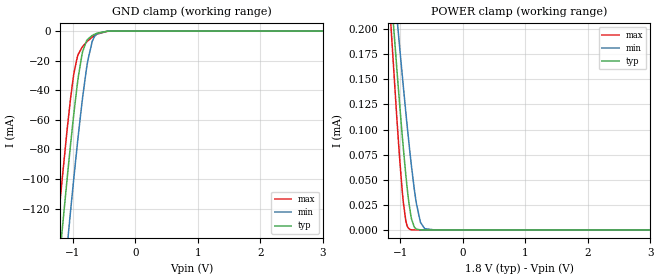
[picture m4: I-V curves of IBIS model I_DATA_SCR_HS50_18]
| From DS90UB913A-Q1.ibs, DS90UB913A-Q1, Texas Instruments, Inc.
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|   Model I_DATA_SCR_HS50_18
[Model] I_DATA_SCR_HS50_18
Model_type Input
Vinl =   0.63
Vinh =   1.17
|   typ   min   max
|   (nom)   (fast)   (slow)
C_comp   0.5298pF   0.3665pF   0.5298pF
[Temperature Range]   25.000   105.000   -40.000
[Voltage Range]   1.800V   1.7100V   1.8900V
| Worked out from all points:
|   GND clamp passes 1 mA (typ) near -0.56 V on its own axis
[GND Clamp]
|   Voltage   I(typ)   I(min)   I(max)
-1.8V     -430.9mA   -477mA     -396.6mA
-1.238V   -164.5mA   -211.3mA   -129.6mA
-1.174V   -135.2mA   -181.7mA   -100.7mA
-1.093V   -99.54mA   -145.4mA   -66.37mA
-1.039V   -76.81mA   -121.8mA   -45.69mA
-984.6mV  -55.39mA   -98.86mA   -28.59mA
-930.6mV  -36.12mA   -76.78mA   -17.61mA
-855mV    -15.77mA   -48.21mA   -11.06mA
-763.2mV  -5.498mA   -20.14mA   -6.658mA
-687.6mV  -2.877mA   -6.556mA   -3.945mA
-450mV    -97.64uA   -77.9uA    -176.8uA
3.595V    0A         0A         0A
[POWER Clamp]
|   Voltage   I(typ)   I(min)   I(max)
-1.8V     803.7uA    754.7uA    897.4uA
-1.157V   241.8uA    282.5uA    208.5uA
-1.055V   157.9uA    210.7uA    108.4uA
-1.012V   124.1uA    181.2uA    70.17uA
-952.2mV  80.3uA     141.7uA    26.6uA
-914.4mV  55uA       117.4uA    9.25uA
-865.8mV  27.6uA     87.52uA    1.228uA
-822.6mV  10.92uA    62.89uA    149.1nA
-747mV    921.8nA    26.99uA    1.513nA
-682.2mV  75.41nA    8.215uA    0A
-612mV    3.441nA    1.296uA    0A
3.595V    0A         0A         0A
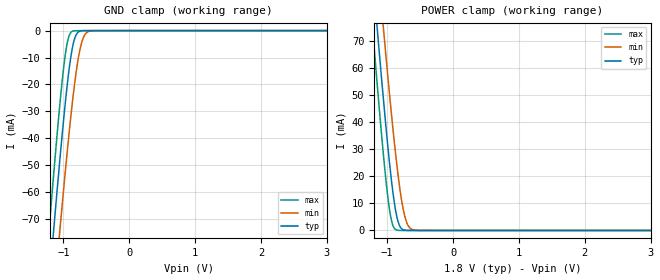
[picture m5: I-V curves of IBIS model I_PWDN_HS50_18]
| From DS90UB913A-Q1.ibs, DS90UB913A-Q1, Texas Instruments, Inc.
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|   Model I_PWDN_HS50_18
[Model]   I_PWDN_HS50_18
Model_type   Input
Vinl = 0.63V
Vinh = 1.17V
|   typ   min   max
|   (nom)   (weak)   (fast)
C_comp   0.5928pF   0.5928pF   0.5928pF
[Voltage Range]   1.800V   1.710V   1.890V
[Temperature Range]   25.0   105.0   -40.0
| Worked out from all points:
|   GND clamp passes 1 mA (typ) near -0.79 V on its own axis
|   POWER clamp passes 1 mA (typ) near -0.79 V on its own axis
[GND Clamp]
|   Voltage   I(typ)   I(min)   I(max)
-1.8V     -270.9mA   -291mA     -255.6mA
-1.228V   -97.1mA    -122.7mA   -76.77mA
-1.201V   -89.21mA   -115mA     -68.71mA
-1.147V   -73.63mA   -99.73mA   -52.87mA
-1.055V   -48.06mA   -74.39mA   -27.51mA
-957.6mV  -23.54mA   -48.82mA   -6.663mA
-871.2mV  -7.328mA   -28.21mA   -335.2uA
-811.8mV  -1.781mA   -16.28mA   -25.67uA
-741.6mV  -161.6uA   -6.205mA   -6.921uA
-682.2mV  -20.1uA    -1.83mA    -5.854uA
-601.2mV  -4.02uA    -199.2uA   -5.127uA
3.595V    6.712uA    3.483uA    12.03uA
[POWER Clamp]
|   Voltage   I(typ)   I(min)   I(max)
-1.8V     270.2mA    290.2mA    254.8mA
-1.228V   96.77mA    122.3mA    76.49mA
-1.201V   88.9mA     114.6mA    68.45mA
-1.147V   73.36mA    99.39mA    52.65mA
-1.055V   47.86mA    74.11mA    27.37mA
-957.6mV  23.41mA    48.61mA    6.6mA
-871.2mV  7.262mA    28.06mA    325.8uA
-811.8mV  1.758mA    16.17mA    20.65uA
-741.6mV  156.5uA    6.146mA    2.661uA
-682.2mV  17.07uA    1.807mA    2.011uA
-601.2mV  1.608uA    195uA      1.824uA
3.595V    0A         0A         0A
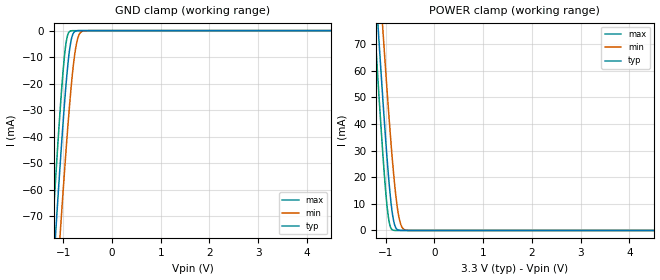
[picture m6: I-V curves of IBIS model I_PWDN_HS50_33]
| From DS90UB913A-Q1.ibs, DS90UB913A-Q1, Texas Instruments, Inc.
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|   Model I_PWDN_HS50_33
[Model]   I_PWDN_HS50_33
Model_type   Input
Vinl = 0.8V
Vinh = 2.0V
|   typ   min   max
|   (nom)   (weak)   (fast)
C_comp   0.5928pF   0.5928pF   0.5928pF
[Voltage Range]   3.300V   3.000V   3.600V
[Temperature Range]   25.0   105.0   -40.0
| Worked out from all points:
|   GND clamp passes 1 mA (typ) near -0.79 V on its own axis
|   POWER clamp passes 1 mA (typ) near -0.79 V on its own axis
[GND Clamp]
|   Voltage   I(typ)   I(min)   I(max)
-3.3V     -740.6mA   -745.8mA   -738.2mA
-1.231V   -98.06mA   -123.6mA   -77.76mA
-1.221V   -95.16mA   -120.8mA   -74.79mA
-1.171V   -80.77mA   -106.7mA   -60.12mA
-1.142V   -72.26mA   -98.38mA   -51.49mA
-1.063V   -50.17mA   -76.5mA    -29.54mA
-953.7mV  -22.65mA   -47.84mA   -6.095mA
-914.1mV  -14.38mA   -38.09mA   -1.938mA
-854.7mV  -5.279mA   -24.66mA   -158.3uA
-735.9mV  -131.2uA   -5.62mA    -6.724uA
-597.3mV  -3.893uA   -177.7uA   -5.09uA
6.59V     7.865uA    3.955uA    14.61uA
[POWER Clamp]
|   Voltage   I(typ)   I(min)   I(max)
-3.3V     739mA      744.2mA    736.5mA
-1.231V   97.8mA     123.3mA    77.52mA
-1.221V   94.9mA     120.5mA    74.56mA
-1.171V   80.54mA    106.4mA    59.92mA
-1.142V   72.04mA    98.11mA    51.31mA
-1.063V   50mA       76.28mA    29.42mA
-953.7mV  22.55mA    47.67mA    6.048mA
-914.1mV  14.3mA     37.95mA    1.916mA
-854.7mV  5.24mA     24.55mA    149.8uA
-735.9mV  126.1uA    5.58mA     498.8nA
-597.3mV  637nA      174.2uA    50.05nA
6.59V     0A         0A         0A
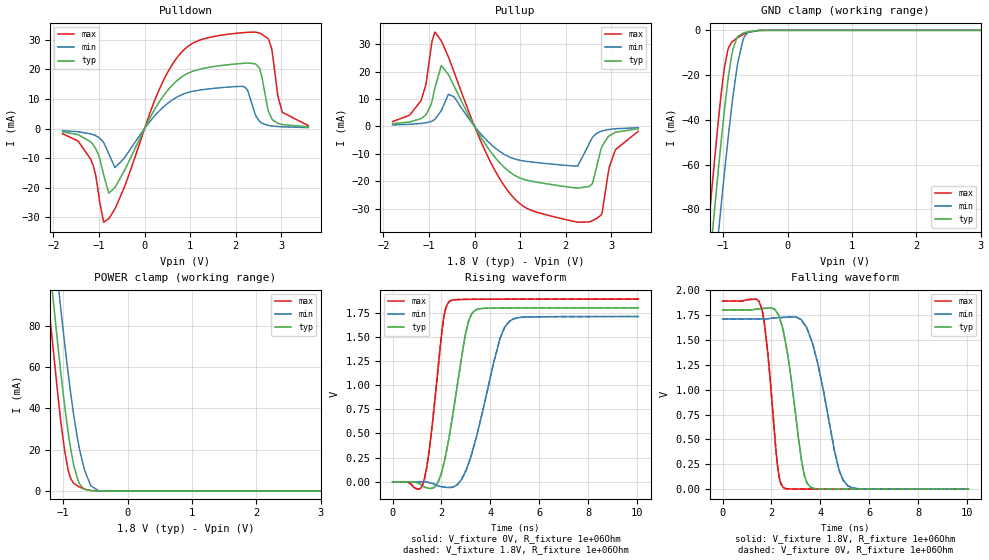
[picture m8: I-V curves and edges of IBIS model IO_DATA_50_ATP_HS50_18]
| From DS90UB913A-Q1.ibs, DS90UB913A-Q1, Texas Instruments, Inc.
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|   Model IO_DATA_50_ATP_HS50_18
[Model]  IO_DATA_50_ATP_HS50_18
Model_type   I/O
Polarity   Non-Inverting
Enable   Active-Low
Vinl =   0.63
Vinh =   1.17
Vmeas = 0.9V
|   typ   min   max
|   (nom)   (fast)   (slow)
C_comp   1.107pF   1.107pF   1.107pF
[Temperature Range]   25.000   105.00   -40.000
[Voltage Range]   1.800V   1.700V   1.900V
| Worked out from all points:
|   slope of the pulldown table from 0 to 0.27 V, typ, clamps not added: 35 ohm
|   slope of the pullup table from 0 to 0.27 V, typ, clamps not added: 37 ohm
|   GND clamp passes 1 mA (typ) near -0.66 V on its own axis
|   POWER clamp passes 1 mA (typ) near -0.68 V on its own axis
|   falling waveform, V_fixture 1.8V, R_fixture 1e+06Ohm: 20-80 % time 589ps typ, 837ps min, 405ps max; typ from 1.8 V to 0 V
|   rising waveform, V_fixture 0V, R_fixture 1e+06Ohm: 20-80 % time 684ps typ, 979ps min, 474ps max; typ from 0 V to 1.8 V
|   rising waveform, V_fixture 1.8V, R_fixture 1e+06Ohm: 20-80 % time 684ps typ, 979ps min, 474ps max; typ from 0 V to 1.8 V
|   falling waveform, V_fixture 0V, R_fixture 1e+06Ohm: 20-80 % time 589ps typ, 837ps min, 405ps max; typ from 1.8 V to 0 V
[Pulldown]
|   Voltage   I(typ)   I(min)   I(max)
-1.8V     -1.155mA   -722uA     -1.746mA
-1.184V   -4.476mA   -1.794mA   -10.29mA
-898.2mV  -15.64mA   -4.698mA   -31.64mA
-784.8mV  -21.82mA   -8.552mA   -30.46mA
-649.8mV  -19.91mA   -13.23mA   -27.17mA
252mV     7.263mA    4.813mA    10.64mA
711mV     16.19mA    10.63mA    23.93mA
2.266V    22.12mA    12.72mA    32.53mA
2.52V     20.5mA     2.492mA    32.28mA
2.817V    2.865mA    818.9uA    24.22mA
3.022V    1.333mA    582uA      5.5mA
3.595V    562.9uA    334.5uA    995.1uA
[GND Clamp]
|   Voltage   I(typ)   I(min)   I(max)
-1.8V     -296.6mA   -318.2mA   -281mA
-1.228V   -109.2mA   -137.1mA   -87.53mA
-1.168V   -90.62mA   -118.9mA   -68.54mA
-1.082V   -64.33mA   -93.04mA   -42.27mA
-1.033V   -50.2mA    -78.83mA   -28.89mA
-979.2mV  -35.42mA   -63.49mA   -16.52mA
-930.6mV  -23.5mA    -50.24mA   -9.211mA
-871.2mV  -11.85mA   -35.13mA   -5.505mA
-768.6mV  -2.676mA   -13.86mA   -3.143mA
-693mV    -1.308mA   -4.468mA   -1.9mA
-450mV    -43.26uA   -33.03uA   -89.99uA
3.595V    0A         0A         0A
[Pullup]
|   Voltage   I(typ)   I(min)   I(max)
-1.8V     960.1uA    529.2uA    1.735mA
-1.179V   2.783mA    1.043mA    9.274mA
-871.2mV  13.95mA    2.526mA    34.4mA
-730.8mV  22.21mA    5.721mA    31.27mA
-450mV    14.71mA    10.77mA    19.81mA
721.8mV   -16mA      -10.84mA   -23.32mA
2.266V    -22.55mA   -14.43mA   -34.99mA
2.585V    -20.92mA   -4.098mA   -34.41mA
2.774V    -8.357mA   -1.812mA   -32.45mA
2.957V    -3.442mA   -1.136mA   -14.88mA
3.092V    -2.174mA   -887.6uA   -8.516mA
3.595V    -844.1uA   -485.2uA   -1.766mA
[POWER Clamp]
|   Voltage   I(typ)   I(min)   I(max)
-1.8V     302.3mA    326mA      285.1mA
-1.217V   111.8mA    141.9mA    88.15mA
-1.19V    103.3mA    133.7mA    79.49mA
-1.076V   68.91mA    99.85mA    44.83mA
-1.044V   59.55mA    90.46mA    35.82mA
-919.8mV  27.87mA    56.5mA     9.944mA
-844.2mV  13.97mA    38.55mA    4.002mA
-779.4mV  6.085mA    25.78mA    2.447mA
-660.6mV  732.7uA    9.487mA    827.9uA
-568.8mV  167.5uA    2.464mA    204.4uA
-450mV    13.54uA    113.5uA    13.22uA
3.595V    0A         0A         0A
[Ramp]
R_load = 1e+06
|   typ   min   max
dV/dt_r   1.07987/6.83959e-10   1.02562/9.78811e-10   1.13394/4.74165e-10
dV/dt_f   1.07988/5.89236e-10   1.02563/8.37013e-10   1.13395/4.05042e-10
[Falling Waveform]
V_fixture = 1.8V
V_fixture_min = 1.71V
V_fixture_max = 1.89V
R_fixture = 1e+06Ohm
C_fixture = 0F
|   Time   V(typ)   V(min)   V(max)
0s        1.8V       1.71V      1.89V
1.621ns   1.814V     1.709V     1.796V
1.851ns   1.819V     1.712V     1.367V
2.234ns   1.77V      1.721V     262.1mV
2.481ns   1.593V     1.725V     16.3mV
3.23ns    284mV      1.698V     1.07mV
3.596ns   20.07mV    1.521V     761.8uV
4.778ns   976.1uV    180.4mV    359.7uV
5.117ns   791.7uV    35.57mV    290.4uV
10.05ns   126.1uV    292.8uV    71.1uV
[Rising Waveform]
V_fixture = 0V
V_fixture_min = 0V
V_fixture_max = 0V
R_fixture = 1e+06Ohm
C_fixture = 0F
|   Time   V(typ)   V(min)   V(max)
0s        41.55uV    165.9uV    9.761uV
1.225ns   -43.42mV   305.9uV    -33.09mV
1.496ns   -67.21mV   -8.484mV   317.7mV
1.887ns   10.44mV    -43.24mV   1.236V
2.091ns   183.3mV    -53.81mV   1.697V
2.313ns   460.7mV    -59.57mV   1.862V
3.23ns    1.735V     282mV      1.887V
4.392ns   1.797V     1.48V      1.889V
4.778ns   1.798V     1.66V      1.889V
10.05ns   1.8V       1.71V      1.89V
[Rising Waveform]
V_fixture = 1.8V
V_fixture_min = 1.71V
V_fixture_max = 1.89V
R_fixture = 1e+06Ohm
C_fixture = 0F
|   Time   V(typ)   V(min)   V(max)
0s        128uV      297uV      70.75uV
1.225ns   -43.45mV   433uV      -32.27mV
1.496ns   -66.51mV   -8.334mV   318.8mV
1.887ns   11.62mV    -42.79mV   1.238V
2.091ns   184.6mV    -53.06mV   1.697V
2.313ns   462.2mV    -58.52mV   1.863V
3.23ns    1.735V     283.8mV    1.888V
4.392ns   1.797V     1.482V     1.889V
4.778ns   1.798V     1.66V      1.889V
10.05ns   1.8V       1.71V      1.89V
[Falling Waveform]
|Gnd
V_fixture = 0V
V_fixture_min = 0V
V_fixture_max = 0V
R_fixture = 1e+06Ohm
C_fixture = 0F
|   Time   V(typ)   V(min)   V(max)
0s        1.8V       1.71V      1.89V
1.621ns   1.814V     1.709V     1.795V
1.851ns   1.819V     1.712V     1.366V
2.234ns   1.77V      1.721V     261.5mV
2.481ns   1.592V     1.725V     16.12mV
3.23ns    283.1mV    1.697V     983.6uV
3.596ns   19.81mV    1.52V      683.4uV
4.778ns   856.7uV    179.4mV    291.9uV
5.117ns   679.6uV    35.13mV    224.4uV
10.05ns   39.67uV    161.9uV    10.1uV
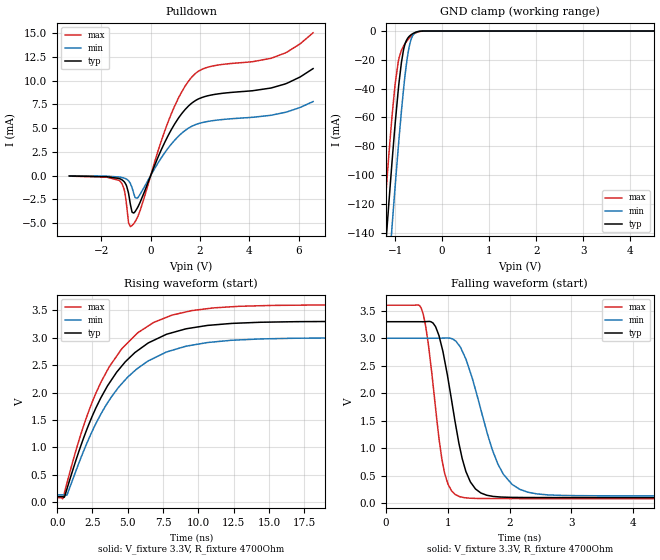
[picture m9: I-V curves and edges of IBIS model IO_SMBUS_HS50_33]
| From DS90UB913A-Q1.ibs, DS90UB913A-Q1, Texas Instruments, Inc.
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|   Model IO_SMBUS_HS50_33
[Model]  IO_SMBUS_HS50_33
Model_type I/O_open_drain
Enable   Active-High
Vinl = 0.8V
Vinh = 2.0V
Vmeas = 1.3V
Vref = 3.3
Rref = 4700
|   typ   min   max
|   (nom)   (fast)   (slow)
C_comp   2.846pF   2.827pF   2.847pF
[Temperature Range]   25.0000   105.000   -40.0000
[Voltage Range]   3.3000V   3.0000V   3.6000V
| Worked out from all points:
|   slope of the pulldown table from 0 to 0.495 V, typ, clamps not added: 161 ohm
|   GND clamp passes 1 mA (typ) near -0.57 V on its own axis
|   falling waveform, V_fixture 3.3V, R_fixture 4700Ohm: 20-80 % time 313ps typ, 462ps min, 222ps max; typ from 3.3 V to 0.101 V
|   rising waveform, V_fixture 3.3V, R_fixture 4700Ohm: 20-80 % time 3.92ns typ, 4.09ns min, 3.8ns max; typ from 0.101 V to 3.3 V
[Pulldown]
|   Voltage   I(typ)   I(min)   I(max)
-3.3V     -50.34uA   -30.88uA   -64.44uA
-1.261V   -330.2uA   -160.2uA   -563uA
-1.073V   -661.8uA   -269.1uA   -1.521mA
-894.3mV  -1.931mA   -564.1uA   -4.993mA
-825mV    -3.027mA   -830.1uA   -5.371mA
-755.7mV  -3.86mA    -1.277mA   -5.263mA
-537.9mV  -3.393mA   -2.366mA   -4.397mA
699.6mV   4.164mA    2.858mA    5.599mA
1.67V     7.624mA    5.188mA    10.36mA
2.442V    8.463mA    5.745mA    11.48mA
4.887V    9.21mA     6.344mA    12.34mA
6.59V     11.25mA    7.782mA    15.02mA
[GND Clamp]
|   Voltage   I(typ)   I(min)   I(max)
-3.3V     -1.167A    -1.21A     -1.135A
-1.251V   -172.2mA   -218.9mA   -137.3mA
-1.162V   -132.2mA   -178.5mA   -98.12mA
-1.073V   -93.94mA   -139.2mA   -61.99mA
-993.3mV  -62.34mA   -105.5mA   -35.34mA
-933.9mV  -41.3mA    -81.43mA   -21.56mA
-825mV    -13.83mA   -41.91mA   -10.68mA
-765.6mV  -6.993mA   -24.57mA   -7.626mA
-706.2mV  -3.93mA    -11.88mA   -5.147mA
-646.8mV  -2.277mA   -4.634mA   -3.183mA
-577.5mV  -1.054mA   -1.289mA   -1.568mA
6.59V     0A         0A         0A
[POWER Clamp]
|   Voltage   I(typ)   I(min)   I(max)
-3.3V     0A         0A         0A
0V        0A         0A         0A
6.59V     0A         0A         0A
[Ramp]
R_load = 4700
|   typ   min   max
dV/dt_r   1.91926/3.92426e-09   1.72026/4.09122e-09   2.11028/3.79737e-09
dV/dt_f   1.91925/3.12626e-10   1.72026/4.61695e-10   2.11029/2.21836e-10
[Falling Waveform]
V_fixture = 3.3V
V_fixture_min = 3V
V_fixture_max = 3.6V
R_fixture = 4700Ohm
C_fixture = 0F
|   Time   V(typ)   V(min)   V(max)
0s        3.3V       3V         3.6V
571ps     3.3V       3V         3.554V
805.3ps   3.21V      2.999V     1.732V
1.005ns   2.269V     3.004V     347.1mV
1.235ns   814.6mV    2.77V      109.6mV
1.463ns   249.1mV    2.013V     87.64mV
1.72ns    127.3mV    977.3mV    85.2mV
2.039ns   106.9mV    344.6mV    84.51mV
3.099ns   102.8mV    138mV      83.96mV
150ns     101.2mV    132.9mV    82.86mV
[Rising Waveform]
V_fixture = 3.3V
V_fixture_min = 3V
V_fixture_max = 3.6V
R_fixture = 4700Ohm
C_fixture = 0F
|   Time   V(typ)   V(min)   V(max)
0s        101.2mV    132.9mV    82.86mV
400.9ps   100.1mV    132.9mV    68.16mV
703.5ps   252.4mV    137.1mV    361.1mV
1.611ns   982.9mV    764.7mV    1.186V
2.589ns   1.632V     1.354V     1.896V
3.677ns   2.166V     1.856V     2.466V
4.566ns   2.482V     2.16V      2.797V
6.834ns   2.953V     2.627V     3.281V
11.07ns   3.235V     2.924V     3.546V
150ns     3.3V       3V         3.6V
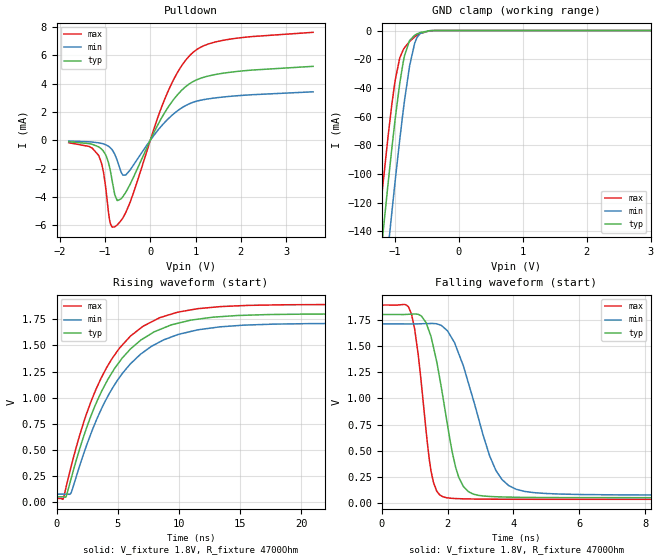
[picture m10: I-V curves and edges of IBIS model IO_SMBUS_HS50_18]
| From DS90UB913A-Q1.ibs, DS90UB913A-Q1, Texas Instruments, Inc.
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|   Model IO_SMBUS_HS50_18
[Model]  IO_SMBUS_HS50_18
Model_type I/O_open_drain
Enable   Active-High
Vinl = 0.63V
Vinh = 1.17V
Vmeas = 0.9V
Vref = 1.8V
Rref = 4700
|   typ   min   max
|   (nom)   (fast)   (slow)
C_comp   2.846pF   2.827pF   2.847pF
[Temperature Range]   25.0000   105.000   -40.0000
[Voltage Range]   1.8000V   1.7000V   1.9000V
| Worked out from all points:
|   slope of the pulldown table from 0 to 0.27 V, typ, clamps not added: 159 ohm
|   GND clamp passes 1 mA (typ) near -0.55 V on its own axis
|   falling waveform, V_fixture 1.8V, R_fixture 4700Ohm: 20-80 % time 605ps typ, 953ps min, 387ps max; typ from 1.8 V to 0.054 V
|   rising waveform, V_fixture 1.8V, R_fixture 4700Ohm: 20-80 % time 4.31ns typ, 4.54ns min, 4.17ns max; typ from 0.054 V to 1.8 V
[Pulldown]
|   Voltage   I(typ)   I(min)   I(max)
-1.8V     -104.1uA   -53.41uA   -171.3uA
-1.141V   -461.7uA   -179.9uA   -1.065mA
-1.028V   -797.8uA   -264.8uA   -2.355mA
-898.2mV  -1.902mA   -481.7uA   -5.632mA
-784.8mV  -3.843mA   -977.1uA   -6.124mA
-725.4mV  -4.267mA   -1.471mA   -5.973mA
-541.8mV  -3.682mA   -2.457mA   -5.115mA
306mV     1.89mA     1.222mA    2.806mA
608.4mV   3.247mA    2.103mA    4.837mA
910.8mV   4.087mA    2.646mA    6.118mA
1.667V    4.769mA    3.078mA    7.102mA
3.595V    5.227mA    3.427mA    7.633mA
[GND Clamp]
|   Voltage   I(typ)   I(min)   I(max)
-1.8V     -431.9mA   -478.2mA   -397.4mA
-1.255V   -173.9mA   -220.7mA   -139.1mA
-1.19V    -144.7mA   -191.2mA   -110.3mA
-1.103V   -107mA     -152.7mA   -74.01mA
-1.044V   -82.23mA   -126.9mA   -51.58mA
-990mV    -61.1mA    -104.1mA   -34.41mA
-925.2mV  -38.5mA    -78.02mA   -20.11mA
-865.8mV  -21.96mA   -55.8mA    -13.4mA
-763.2mV  -6.818mA   -23.95mA   -7.516mA
-655.2mV  -2.467mA   -5.353mA   -3.428mA
-428.4mV  -66.97uA   -62.81uA   -122.5uA
3.595V    0A         0A         0A
[POWER Clamp]
|   Voltage   I(typ)   I(min)   I(max)
-1.8V     0A         0A         0A
3.6mV     0A         0A         0A
3.595V    0A         0A         0A
[Ramp]
R_load = 4700
|   typ   min   max
dV/dt_r   1.04751/4.31495e-09   0.978493/4.536e-09   1.11089/4.17131e-09
dV/dt_f   1.04751/6.0476e-10   0.97849/9.52756e-10   1.11088/3.8715e-10
[Falling Waveform]
V_fixture = 1.8V
V_fixture_min = 1.71V
V_fixture_max = 1.89V
R_fixture = 4700Ohm
C_fixture = 0F
|   Time   V(typ)   V(min)   V(max)
0s        1.8V       1.71V      1.89V
900.1ps   1.803V     1.709V     1.806V
1.104ns   1.801V     1.711V     1.42V
1.345ns   1.723V     1.713V     692.4mV
1.665ns   1.355V     1.711V     118.7mV
2.253ns   333.4mV    1.496V     45.8mV
2.627ns   112.2mV    1.152V     42.39mV
3.652ns   61.11mV    227.4mV    39.41mV
5.384ns   55.11mV    89.16mV    38.82mV
150ns     54.15mV    79.15mV    38.53mV
[Rising Waveform]
V_fixture = 1.8V
V_fixture_min = 1.71V
V_fixture_max = 1.89V
R_fixture = 4700Ohm
C_fixture = 0F
|   Time   V(typ)   V(min)   V(max)
0s        54.15mV    79.15mV    38.53mV
555.4ps   54.26mV    79.18mV    37.16mV
798.1ps   59.28mV    79.19mV    154.8mV
1.198ns   229.6mV    93.82mV    346mV
3.221ns   942.4mV    775.9mV    1.079V
5.122ns   1.34V      1.189V     1.47V
7.738ns   1.612V     1.489V     1.722V
11.52ns   1.749V     1.648V     1.85V
24.8ns    1.8V       1.71V      1.889V
150ns     1.8V       1.71V      1.89V
